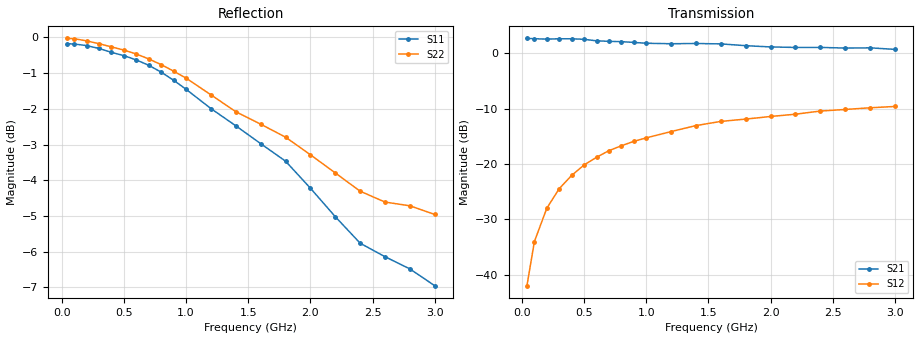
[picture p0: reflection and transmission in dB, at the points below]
! Filename:  BFS25AH.S2P  Version:  4.0
! NXP part #: BFS25A  Date: Jun 1994
! Bias condition: Vce=3V, Ic=0.5mA
#  MHz  S  MA  R  50
! Freq  S11  S21  S12  S22  !GUM [dB]
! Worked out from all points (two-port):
!   21 points, 40 MHz to 3 GHz, reference 50 ohm
!   highest |S21| = 2.65 dB at 40 MHz (marker M1); lowest = 0.7 dB at 3 GHz (marker M2)
!   |S21| within 3 dB of the highest: start of sweep to end of sweep
!   lowest |S11| = -7.0 dB at 3 GHz (marker M3), VSWR 2.63, Z = 48.1 - j49.2 ohm
!   |S11| at or under -10 dB: nowhere
!   |S22| runs from -5.0 to 0.0 dB; largest |S21 - S12| = 1.4
!   S11 on the Smith chart (normalised r, x): 40 MHz: 48, -49; 500 MHz: 1.64, -7.23; 1 GHz: 1.30, -3.60; 1.6 GHz: 1.07, -2.09; 2.2 GHz: 1.11, -1.42; 3 GHz: 0.96, -0.98
40  0.98 -1.2  1.356 177.4  0.008 88.4  0.997 -1.2
100  0.979 -2.9  1.346 174.1  0.02 86.0  0.996 -3.0
200  0.974 -6.0  1.335 168.5  0.04 82.9  0.989 -6.0
300  0.965 -9.1  1.345 163.2  0.06 80.2  0.98 -9.0
400  0.953 -12.2  1.345 158.1  0.079 77.6  0.97 -12.1
500  0.943 -15.0  1.329 153.5  0.098 75.4  0.96 -15.1
600  0.93 -17.8  1.288 148.9  0.115 73.2  0.948 -17.8
700  0.914 -20.4  1.275 144.4  0.132 71.2  0.933 -20.4
800  0.894 -22.9  1.266 139.9  0.146 69.2  0.916 -22.6
900  0.871 -25.4  1.247 135.2  0.16 66.9  0.897 -24.7
1000  0.846 -27.8  1.225 130.9  0.172 64.6  0.877 -26.8
1200  0.795 -33.1  1.213 123.0  0.196 60.2  0.831 -31.1
1400  0.752 -38.4  1.219 115.8  0.222 56.8  0.787 -35.3
1600  0.71 -42.8  1.209 109.5  0.242 53.7  0.756 -39.2
1800  0.671 -45.7  1.165 104.5  0.254 52.0  0.725 -42.3
2000  0.615 -48.4  1.135 98.0  0.268 49.7  0.685 -44.6
2200  0.561 -51.7  1.123 92.6  0.281 47.7  0.646 -47.4
2400  0.515 -56.4  1.124 86.2  0.3 45.2  0.609 -51.4
2600  0.493 -61.8  1.109 82.8  0.31 43.2  0.588 -55.7
2800  0.474 -65.0  1.114 79.5  0.321 43.2  0.581 -58.5
3000  0.449 -65.6  1.079 75.7  0.33 42.3  0.565 -60.0
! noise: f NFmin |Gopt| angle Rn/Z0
500  1.6  0.886  2  2.6
1000  1.8  0.839  9  2.6
2000  2  0.718  29  1.8
